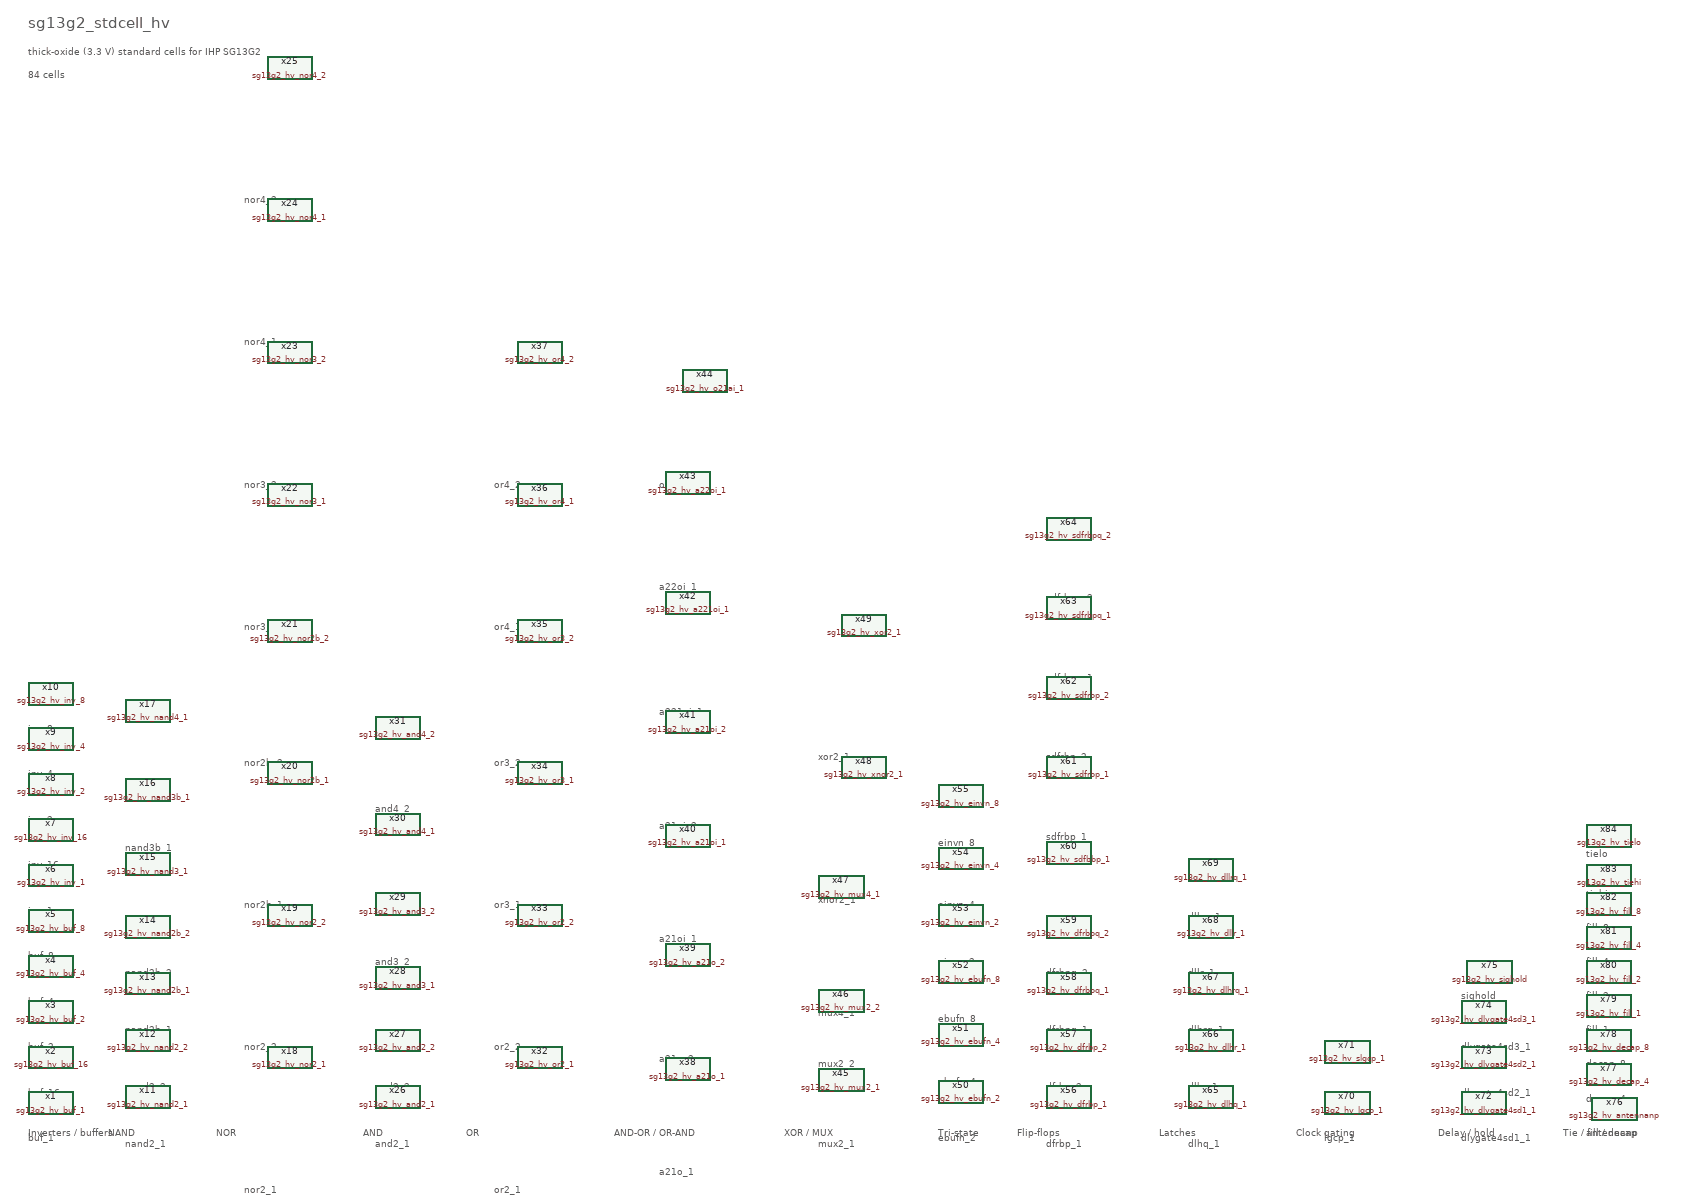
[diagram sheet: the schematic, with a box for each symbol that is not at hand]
v {xschem version=3.4.7 file_version=1.2
* sg13g2_stdcell_hv -- thick-oxide (3.3 V) standard cell gallery.
*
* One instance of every cell in the library, grouped by function.
* The thick-oxide counterpart of the PDK's IHP130_stdcells.sch.
*
* Generated by work/gen_gallery.py -- do not edit by hand.
}
G {}
K {}
V {}
S {}
E {}
T {sg13g2_stdcell_hv} 0 -1990 0 0 0.8 0.8 {layer=4}
T {thick-oxide (3.3 V) standard cells for IHP SG13G2} 0 -1940 0 0 0.4 0.4 {layer=4}
T {84 cells} 0 -1900 0 0 0.4 0.4 {layer=4}
T {Inverters / buffers} 0 -40 0 0 0.4 0.4 {layer=4}
C {sg13g2_hv_buf_1.sym} 40 -80 0 0 {name=x1 VDD=VDD VSS=VSS prefix=sg13g2_hv_}
T {buf_1} 0 -30 0 0 0.25 0.25 {layer=15}
C {sg13g2_hv_buf_16.sym} 40 -160 0 0 {name=x2 VDD=VDD VSS=VSS prefix=sg13g2_hv_}
T {buf_16} 0 -110 0 0 0.25 0.25 {layer=15}
C {sg13g2_hv_buf_2.sym} 40 -240 0 0 {name=x3 VDD=VDD VSS=VSS prefix=sg13g2_hv_}
T {buf_2} 0 -190 0 0 0.25 0.25 {layer=15}
C {sg13g2_hv_buf_4.sym} 40 -320 0 0 {name=x4 VDD=VDD VSS=VSS prefix=sg13g2_hv_}
T {buf_4} 0 -270 0 0 0.25 0.25 {layer=15}
C {sg13g2_hv_buf_8.sym} 40 -400 0 0 {name=x5 VDD=VDD VSS=VSS prefix=sg13g2_hv_}
T {buf_8} 0 -350 0 0 0.25 0.25 {layer=15}
C {sg13g2_hv_inv_1.sym} 40 -480 0 0 {name=x6 VDD=VDD VSS=VSS prefix=sg13g2_hv_}
T {inv_1} 0 -430 0 0 0.25 0.25 {layer=15}
C {sg13g2_hv_inv_16.sym} 40 -560 0 0 {name=x7 VDD=VDD VSS=VSS prefix=sg13g2_hv_}
T {inv_16} 0 -510 0 0 0.25 0.25 {layer=15}
C {sg13g2_hv_inv_2.sym} 40 -640 0 0 {name=x8 VDD=VDD VSS=VSS prefix=sg13g2_hv_}
T {inv_2} 0 -590 0 0 0.25 0.25 {layer=15}
C {sg13g2_hv_inv_4.sym} 40 -720 0 0 {name=x9 VDD=VDD VSS=VSS prefix=sg13g2_hv_}
T {inv_4} 0 -670 0 0 0.25 0.25 {layer=15}
C {sg13g2_hv_inv_8.sym} 40 -800 0 0 {name=x10 VDD=VDD VSS=VSS prefix=sg13g2_hv_}
T {inv_8} 0 -750 0 0 0.25 0.25 {layer=15}
T {NAND} 140 -40 0 0 0.4 0.4 {layer=4}
C {sg13g2_hv_nand2_1.sym} 210 -90 0 0 {name=x11 VDD=VDD VSS=VSS prefix=sg13g2_hv_}
T {nand2_1} 170 -20 0 0 0.25 0.25 {layer=15}
C {sg13g2_hv_nand2_2.sym} 210 -190 0 0 {name=x12 VDD=VDD VSS=VSS prefix=sg13g2_hv_}
T {nand2_2} 170 -120 0 0 0.25 0.25 {layer=15}
C {sg13g2_hv_nand2b_1.sym} 210 -290 0 0 {name=x13 VDD=VDD VSS=VSS prefix=sg13g2_hv_}
T {nand2b_1} 170 -220 0 0 0.25 0.25 {layer=15}
C {sg13g2_hv_nand2b_2.sym} 210 -390 0 0 {name=x14 VDD=VDD VSS=VSS prefix=sg13g2_hv_}
T {nand2b_2} 170 -320 0 0 0.25 0.25 {layer=15}
C {sg13g2_hv_nand3_1.sym} 210 -500 0 0 {name=x15 VDD=VDD VSS=VSS prefix=sg13g2_hv_}
T {nand3_1} 170 -410 0 0 0.25 0.25 {layer=15}
C {sg13g2_hv_nand3b_1.sym} 210 -630 0 0 {name=x16 VDD=VDD VSS=VSS prefix=sg13g2_hv_}
T {nand3b_1} 170 -540 0 0 0.25 0.25 {layer=15}
C {sg13g2_hv_nand4_1.sym} 210 -770 0 0 {name=x17 VDD=VDD VSS=VSS prefix=sg13g2_hv_}
T {nand4_1} 170 -640 0 0 0.25 0.25 {layer=15}
T {NOR} 330 -40 0 0 0.4 0.4 {layer=4}
C {sg13g2_hv_nor2_1.sym} 460 -160 0 0 {name=x18 VDD=VDD VSS=VSS prefix=sg13g2_hv_}
T {nor2_1} 380 60 0 0 0.25 0.25 {layer=15}
C {sg13g2_hv_nor2_2.sym} 460 -410 0 0 {name=x19 VDD=VDD VSS=VSS prefix=sg13g2_hv_}
T {nor2_2} 380 -190 0 0 0.25 0.25 {layer=15}
C {sg13g2_hv_nor2b_1.sym} 460 -660 0 0 {name=x20 VDD=VDD VSS=VSS prefix=sg13g2_hv_}
T {nor2b_1} 380 -440 0 0 0.25 0.25 {layer=15}
C {sg13g2_hv_nor2b_2.sym} 460 -910 0 0 {name=x21 VDD=VDD VSS=VSS prefix=sg13g2_hv_}
T {nor2b_2} 380 -690 0 0 0.25 0.25 {layer=15}
C {sg13g2_hv_nor3_1.sym} 460 -1150 0 0 {name=x22 VDD=VDD VSS=VSS prefix=sg13g2_hv_}
T {nor3_1} 380 -930 0 0 0.25 0.25 {layer=15}
C {sg13g2_hv_nor3_2.sym} 460 -1400 0 0 {name=x23 VDD=VDD VSS=VSS prefix=sg13g2_hv_}
T {nor3_2} 380 -1180 0 0 0.25 0.25 {layer=15}
C {sg13g2_hv_nor4_1.sym} 460 -1650 0 0 {name=x24 VDD=VDD VSS=VSS prefix=sg13g2_hv_}
T {nor4_1} 380 -1430 0 0 0.25 0.25 {layer=15}
C {sg13g2_hv_nor4_2.sym} 460 -1900 0 0 {name=x25 VDD=VDD VSS=VSS prefix=sg13g2_hv_}
T {nor4_2} 380 -1680 0 0 0.25 0.25 {layer=15}
T {AND} 590 -40 0 0 0.4 0.4 {layer=4}
C {sg13g2_hv_and2_1.sym} 650 -90 0 0 {name=x26 VDD=VDD VSS=VSS prefix=sg13g2_hv_}
T {and2_1} 610 -20 0 0 0.25 0.25 {layer=15}
C {sg13g2_hv_and2_2.sym} 650 -190 0 0 {name=x27 VDD=VDD VSS=VSS prefix=sg13g2_hv_}
T {and2_2} 610 -120 0 0 0.25 0.25 {layer=15}
C {sg13g2_hv_and3_1.sym} 650 -300 0 0 {name=x28 VDD=VDD VSS=VSS prefix=sg13g2_hv_}
T {and3_1} 610 -210 0 0 0.25 0.25 {layer=15}
C {sg13g2_hv_and3_2.sym} 650 -430 0 0 {name=x29 VDD=VDD VSS=VSS prefix=sg13g2_hv_}
T {and3_2} 610 -340 0 0 0.25 0.25 {layer=15}
C {sg13g2_hv_and4_1.sym} 650 -570 0 0 {name=x30 VDD=VDD VSS=VSS prefix=sg13g2_hv_}
T {and4_1} 610 -440 0 0 0.25 0.25 {layer=15}
C {sg13g2_hv_and4_2.sym} 650 -740 0 0 {name=x31 VDD=VDD VSS=VSS prefix=sg13g2_hv_}
T {and4_2} 610 -610 0 0 0.25 0.25 {layer=15}
T {OR} 770 -40 0 0 0.4 0.4 {layer=4}
C {sg13g2_hv_or2_1.sym} 900 -160 0 0 {name=x32 VDD=VDD VSS=VSS prefix=sg13g2_hv_}
T {or2_1} 820 60 0 0 0.25 0.25 {layer=15}
C {sg13g2_hv_or2_2.sym} 900 -410 0 0 {name=x33 VDD=VDD VSS=VSS prefix=sg13g2_hv_}
T {or2_2} 820 -190 0 0 0.25 0.25 {layer=15}
C {sg13g2_hv_or3_1.sym} 900 -660 0 0 {name=x34 VDD=VDD VSS=VSS prefix=sg13g2_hv_}
T {or3_1} 820 -440 0 0 0.25 0.25 {layer=15}
C {sg13g2_hv_or3_2.sym} 900 -910 0 0 {name=x35 VDD=VDD VSS=VSS prefix=sg13g2_hv_}
T {or3_2} 820 -690 0 0 0.25 0.25 {layer=15}
C {sg13g2_hv_or4_1.sym} 900 -1150 0 0 {name=x36 VDD=VDD VSS=VSS prefix=sg13g2_hv_}
T {or4_1} 820 -930 0 0 0.25 0.25 {layer=15}
C {sg13g2_hv_or4_2.sym} 900 -1400 0 0 {name=x37 VDD=VDD VSS=VSS prefix=sg13g2_hv_}
T {or4_2} 820 -1180 0 0 0.25 0.25 {layer=15}
T {AND-OR / OR-AND} 1030 -40 0 0 0.4 0.4 {layer=4}
C {sg13g2_hv_a21o_1.sym} 1160 -140 0 0 {name=x38 VDD=VDD VSS=VSS prefix=sg13g2_hv_}
T {a21o_1} 1110 30 0 0 0.25 0.25 {layer=15}
C {sg13g2_hv_a21o_2.sym} 1160 -340 0 0 {name=x39 VDD=VDD VSS=VSS prefix=sg13g2_hv_}
T {a21o_2} 1110 -170 0 0 0.25 0.25 {layer=15}
C {sg13g2_hv_a21oi_1.sym} 1160 -550 0 0 {name=x40 VDD=VDD VSS=VSS prefix=sg13g2_hv_}
T {a21oi_1} 1110 -380 0 0 0.25 0.25 {layer=15}
C {sg13g2_hv_a21oi_2.sym} 1160 -750 0 0 {name=x41 VDD=VDD VSS=VSS prefix=sg13g2_hv_}
T {a21oi_2} 1110 -580 0 0 0.25 0.25 {layer=15}
C {sg13g2_hv_a221oi_1.sym} 1160 -960 0 0 {name=x42 VDD=VDD VSS=VSS prefix=sg13g2_hv_}
T {a221oi_1} 1110 -780 0 0 0.25 0.25 {layer=15}
C {sg13g2_hv_a22oi_1.sym} 1160 -1170 0 0 {name=x43 VDD=VDD VSS=VSS prefix=sg13g2_hv_}
T {a22oi_1} 1110 -1000 0 0 0.25 0.25 {layer=15}
C {sg13g2_hv_o21ai_1.sym} 1190 -1350 0 0 {name=x44 VDD=VDD VSS=VSS prefix=sg13g2_hv_}
T {o21ai_1} 1110 -1180 0 0 0.25 0.25 {layer=15}
T {XOR / MUX} 1330 -40 0 0 0.4 0.4 {layer=4}
C {sg13g2_hv_mux2_1.sym} 1430 -120 0 0 {name=x45 VDD=VDD VSS=VSS prefix=sg13g2_hv_}
T {mux2_1} 1390 -20 0 0 0.25 0.25 {layer=15}
C {sg13g2_hv_mux2_2.sym} 1430 -260 0 0 {name=x46 VDD=VDD VSS=VSS prefix=sg13g2_hv_}
T {mux2_2} 1390 -160 0 0 0.25 0.25 {layer=15}
C {sg13g2_hv_mux4_1.sym} 1430 -460 0 0 {name=x47 VDD=VDD VSS=VSS prefix=sg13g2_hv_}
T {mux4_1} 1390 -250 0 0 0.25 0.25 {layer=15}
C {sg13g2_hv_xnor2_1.sym} 1470 -670 0 0 {name=x48 VDD=VDD VSS=VSS prefix=sg13g2_hv_}
T {xnor2_1} 1390 -450 0 0 0.25 0.25 {layer=15}
C {sg13g2_hv_xor2_1.sym} 1470 -920 0 0 {name=x49 VDD=VDD VSS=VSS prefix=sg13g2_hv_}
T {xor2_1} 1390 -700 0 0 0.25 0.25 {layer=15}
T {Tri-state} 1600 -40 0 0 0.4 0.4 {layer=4}
C {sg13g2_hv_ebufn_2.sym} 1640 -100 0 0 {name=x50 VDD=VDD VSS=VSS prefix=sg13g2_hv_}
T {ebufn_2} 1600 -30 0 0 0.25 0.25 {layer=15}
C {sg13g2_hv_ebufn_4.sym} 1640 -200 0 0 {name=x51 VDD=VDD VSS=VSS prefix=sg13g2_hv_}
T {ebufn_4} 1600 -130 0 0 0.25 0.25 {layer=15}
C {sg13g2_hv_ebufn_8.sym} 1640 -310 0 0 {name=x52 VDD=VDD VSS=VSS prefix=sg13g2_hv_}
T {ebufn_8} 1600 -240 0 0 0.25 0.25 {layer=15}
C {sg13g2_hv_einvn_2.sym} 1640 -410 0 0 {name=x53 VDD=VDD VSS=VSS prefix=sg13g2_hv_}
T {einvn_2} 1600 -340 0 0 0.25 0.25 {layer=15}
C {sg13g2_hv_einvn_4.sym} 1640 -510 0 0 {name=x54 VDD=VDD VSS=VSS prefix=sg13g2_hv_}
T {einvn_4} 1600 -440 0 0 0.25 0.25 {layer=15}
C {sg13g2_hv_einvn_8.sym} 1640 -620 0 0 {name=x55 VDD=VDD VSS=VSS prefix=sg13g2_hv_}
T {einvn_8} 1600 -550 0 0 0.25 0.25 {layer=15}
T {Flip-flops} 1740 -40 0 0 0.4 0.4 {layer=4}
C {sg13g2_hv_dfrbp_1.sym} 1830 -90 0 0 {name=x56 VDD=VDD VSS=VSS prefix=sg13g2_hv_}
T {dfrbp_1} 1790 -20 0 0 0.25 0.25 {layer=15}
C {sg13g2_hv_dfrbp_2.sym} 1830 -190 0 0 {name=x57 VDD=VDD VSS=VSS prefix=sg13g2_hv_}
T {dfrbp_2} 1790 -120 0 0 0.25 0.25 {layer=15}
C {sg13g2_hv_dfrbpq_1.sym} 1830 -290 0 0 {name=x58 VDD=VDD VSS=VSS prefix=sg13g2_hv_}
T {dfrbpq_1} 1790 -220 0 0 0.25 0.25 {layer=15}
C {sg13g2_hv_dfrbpq_2.sym} 1830 -390 0 0 {name=x59 VDD=VDD VSS=VSS prefix=sg13g2_hv_}
T {dfrbpq_2} 1790 -320 0 0 0.25 0.25 {layer=15}
C {sg13g2_hv_sdfbbp_1.sym} 1830 -520 0 0 {name=x60 VDD=VDD VSS=VSS prefix=sg13g2_hv_}
T {sdfbbp_1} 1790 -390 0 0 0.25 0.25 {layer=15}
C {sg13g2_hv_sdfrbp_1.sym} 1830 -670 0 0 {name=x61 VDD=VDD VSS=VSS prefix=sg13g2_hv_}
T {sdfrbp_1} 1790 -560 0 0 0.25 0.25 {layer=15}
C {sg13g2_hv_sdfrbp_2.sym} 1830 -810 0 0 {name=x62 VDD=VDD VSS=VSS prefix=sg13g2_hv_}
T {sdfrbp_2} 1790 -700 0 0 0.25 0.25 {layer=15}
C {sg13g2_hv_sdfrbpq_1.sym} 1830 -950 0 0 {name=x63 VDD=VDD VSS=VSS prefix=sg13g2_hv_}
T {sdfrbpq_1} 1790 -840 0 0 0.25 0.25 {layer=15}
C {sg13g2_hv_sdfrbpq_2.sym} 1830 -1090 0 0 {name=x64 VDD=VDD VSS=VSS prefix=sg13g2_hv_}
T {sdfrbpq_2} 1790 -980 0 0 0.25 0.25 {layer=15}
T {Latches} 1990 -40 0 0 0.4 0.4 {layer=4}
C {sg13g2_hv_dlhq_1.sym} 2080 -90 0 0 {name=x65 VDD=VDD VSS=VSS prefix=sg13g2_hv_}
T {dlhq_1} 2040 -20 0 0 0.25 0.25 {layer=15}
C {sg13g2_hv_dlhr_1.sym} 2080 -190 0 0 {name=x66 VDD=VDD VSS=VSS prefix=sg13g2_hv_}
T {dlhr_1} 2040 -120 0 0 0.25 0.25 {layer=15}
C {sg13g2_hv_dlhrq_1.sym} 2080 -290 0 0 {name=x67 VDD=VDD VSS=VSS prefix=sg13g2_hv_}
T {dlhrq_1} 2040 -220 0 0 0.25 0.25 {layer=15}
C {sg13g2_hv_dllr_1.sym} 2080 -390 0 0 {name=x68 VDD=VDD VSS=VSS prefix=sg13g2_hv_}
T {dllr_1} 2040 -320 0 0 0.25 0.25 {layer=15}
C {sg13g2_hv_dllrq_1.sym} 2080 -490 0 0 {name=x69 VDD=VDD VSS=VSS prefix=sg13g2_hv_}
T {dllrq_1} 2040 -420 0 0 0.25 0.25 {layer=15}
T {Clock gating} 2230 -40 0 0 0.4 0.4 {layer=4}
C {sg13g2_hv_lgcp_1.sym} 2320 -80 0 0 {name=x70 VDD=VDD VSS=VSS prefix=sg13g2_hv_}
T {lgcp_1} 2280 -30 0 0 0.25 0.25 {layer=15}
C {sg13g2_hv_slgcp_1.sym} 2320 -170 0 0 {name=x71 VDD=VDD VSS=VSS prefix=sg13g2_hv_}
T {slgcp_1} 2280 -100 0 0 0.25 0.25 {layer=15}
T {Delay / hold} 2480 -40 0 0 0.4 0.4 {layer=4}
C {sg13g2_hv_dlygate4sd1_1.sym} 2560 -80 0 0 {name=x72 VDD=VDD VSS=VSS prefix=sg13g2_hv_}
T {dlygate4sd1_1} 2520 -30 0 0 0.25 0.25 {layer=15}
C {sg13g2_hv_dlygate4sd2_1.sym} 2560 -160 0 0 {name=x73 VDD=VDD VSS=VSS prefix=sg13g2_hv_}
T {dlygate4sd2_1} 2520 -110 0 0 0.25 0.25 {layer=15}
C {sg13g2_hv_dlygate4sd3_1.sym} 2560 -240 0 0 {name=x74 VDD=VDD VSS=VSS prefix=sg13g2_hv_}
T {dlygate4sd3_1} 2520 -190 0 0 0.25 0.25 {layer=15}
C {sg13g2_hv_sighold.sym} 2570 -310 0 0 {name=x75 VDD=VDD VSS=VSS prefix=sg13g2_hv_}
T {sighold} 2520 -280 0 0 0.25 0.25 {layer=15}
T {Tie / fill / decap} 2700 -40 0 0 0.4 0.4 {layer=4}
C {sg13g2_hv_antennanp.sym} 2790 -70 0 0 {name=x76 VDD=VDD VSS=VSS prefix=sg13g2_hv_}
T {antennanp} 2740 -40 0 0 0.25 0.25 {layer=15}
C {sg13g2_hv_decap_4.sym} 2780 -130 0 0 {name=x77 VDD=VDD VSS=VSS prefix=sg13g2_hv_}
T {decap_4} 2740 -100 0 0 0.25 0.25 {layer=15}
C {sg13g2_hv_decap_8.sym} 2780 -190 0 0 {name=x78 VDD=VDD VSS=VSS prefix=sg13g2_hv_}
T {decap_8} 2740 -160 0 0 0.25 0.25 {layer=15}
C {sg13g2_hv_fill_1.sym} 2780 -250 0 0 {name=x79 VDD=VDD VSS=VSS prefix=sg13g2_hv_}
T {fill_1} 2740 -220 0 0 0.25 0.25 {layer=15}
C {sg13g2_hv_fill_2.sym} 2780 -310 0 0 {name=x80 VDD=VDD VSS=VSS prefix=sg13g2_hv_}
T {fill_2} 2740 -280 0 0 0.25 0.25 {layer=15}
C {sg13g2_hv_fill_4.sym} 2780 -370 0 0 {name=x81 VDD=VDD VSS=VSS prefix=sg13g2_hv_}
T {fill_4} 2740 -340 0 0 0.25 0.25 {layer=15}
C {sg13g2_hv_fill_8.sym} 2780 -430 0 0 {name=x82 VDD=VDD VSS=VSS prefix=sg13g2_hv_}
T {fill_8} 2740 -400 0 0 0.25 0.25 {layer=15}
C {sg13g2_hv_tiehi.sym} 2780 -480 0 0 {name=x83 VDD=VDD VSS=VSS prefix=sg13g2_hv_}
T {tiehi} 2740 -460 0 0 0.25 0.25 {layer=15}
C {sg13g2_hv_tielo.sym} 2780 -550 0 0 {name=x84 VDD=VDD VSS=VSS prefix=sg13g2_hv_}
T {tielo} 2740 -530 0 0 0.25 0.25 {layer=15}
